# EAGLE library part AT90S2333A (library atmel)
MICROCONTROLLER 2 Kbytes FLASH 128 bytes SRAM 128 bytes EEPROM UART 6-channel 10-bit ADC

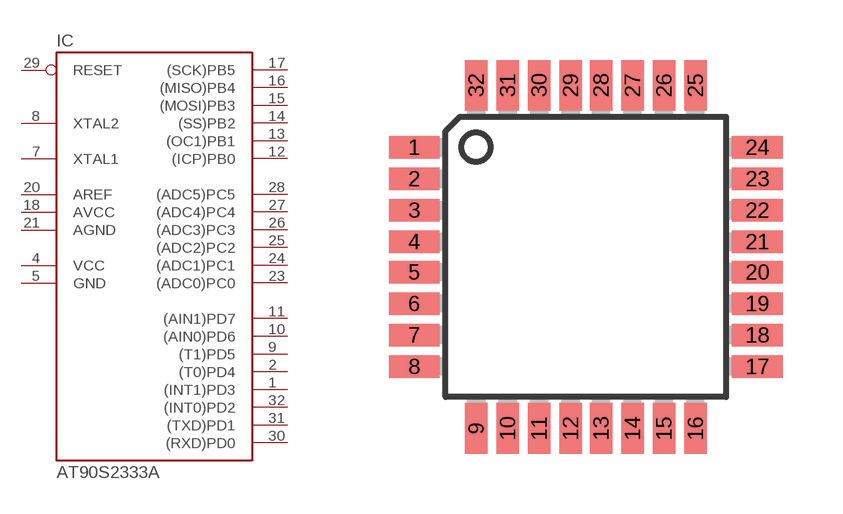
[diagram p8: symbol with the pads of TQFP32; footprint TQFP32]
Designator prefix IC

## AT90S2333A  [TQFP32]
1  (INT1)PD3
2  (T0)PD4
3  NC1  nc
4  VCC  pwr
5  GND  pwr
6  NC2  nc
7  XTAL1
8  XTAL2
9  (T1)PD5
10  (AIN0)PD6
11  (AIN1)PD7
12  (ICP)PB0
13  (OC1)PB1
14  (SS)PB2
15  (MOSI)PB3
16  (MISO)PB4
17  (SCK)PB5
18  AVCC  pwr
19  NC3  nc
20  AREF  pwr
21  AGND  pwr
22  NC4  nc
23  (ADC0)PC0
24  (ADC1)PC1
25  (ADC2)PC2
26  (ADC3)PC3
27  (ADC4)PC4
28  (ADC5)PC5
29  RESET  in
30  (RXD)PD0
31  (TXD)PD1
32  (INT0)PD2

## Footprint TQFP32 (pad centres in mm)
Thin Plasic Quad Flat Package
smd 1.27 x 0.559: 1 -4.293,2.743; 2 -4.293,1.956; 3 -4.293,1.168; 4 -4.293,0.381; 5 -4.293,-0.381; 6 -4.293,-1.168; 7 -4.293,-1.956; 8 -4.293,-2.743; 17 4.293,-2.743; 18 4.293,-1.956; 19 4.293,-1.168; 20 4.293,-0.381; 21 4.293,0.381; 22 4.293,1.168; 23 4.293,1.956; 24 4.293,2.743
smd 0.559 x 1.27: 9 -2.743,-4.293; 10 -1.956,-4.293; 11 -1.168,-4.293; 12 -0.381,-4.293; 13 0.381,-4.293; 14 1.168,-4.293; 15 1.956,-4.293; 16 2.743,-4.293; 25 2.743,4.293; 26 1.956,4.293; 27 1.168,4.293; 28 0.381,4.293; 29 -0.381,4.293; 30 -1.168,4.293; 31 -1.956,4.293; 32 -2.743,4.293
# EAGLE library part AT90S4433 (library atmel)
MICROCONTROLLER 4 Kbytes FLASH 128 bytes SRAM 256 bytes EEPROM UART 6-channel 10 bit ADC

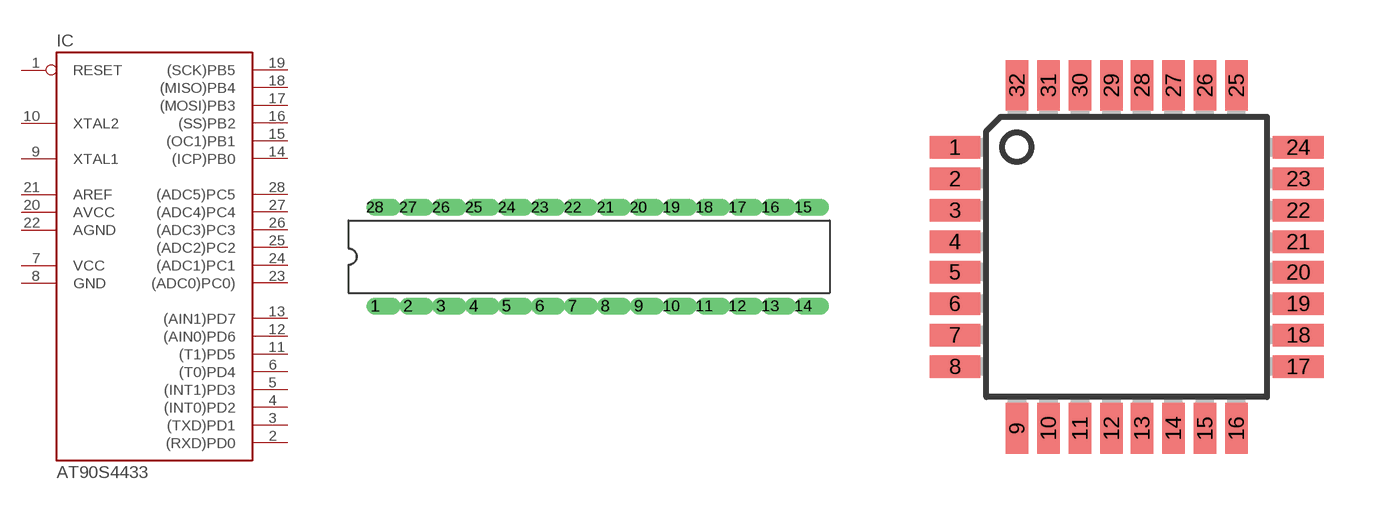
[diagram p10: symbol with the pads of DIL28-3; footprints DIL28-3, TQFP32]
Designator prefix IC

## AT90S4433P  [DIL28-3]
1  RESET  in
2  (RXD)PD0
3  (TXD)PD1
4  (INT0)PD2
5  (INT1)PD3
6  (T0)PD4
7  VCC  pwr
8  GND  pwr
9  XTAL1
10  XTAL2
11  (T1)PD5
12  (AIN0)PD6
13  (AIN1)PD7
14  (ICP)PB0
15  (OC1)PB1
16  (SS)PB2
17  (MOSI)PB3
18  (MISO)PB4
19  (SCK)PB5
20  AVCC  pwr
21  AREF  pwr
22  AGND  pwr
23  (ADC0)PC0)
24  (ADC1)PC1
25  (ADC2)PC2
26  (ADC3)PC3
27  (ADC4)PC4
28  (ADC5)PC5

## AT90S4433A  [TQFP32]
1  (INT1)PD3
2  (T0)PD4
4  VCC  pwr
5  GND  pwr
7  XTAL1
8  XTAL2
9  (T1)PD5
10  (AIN0)PD6
11  (AIN1)PD7
12  (ICP)PB0
13  (OC1)PB1
14  (SS)PB2
15  (MOSI)PB3
16  (MISO)PB4
17  (SCK)PB5
18  AVCC  pwr
20  AREF  pwr
21  AGND  pwr
23  (ADC0)PC0)
24  (ADC1)PC1
25  (ADC2)PC2
26  (ADC3)PC3
27  (ADC4)PC4
28  (ADC5)PC5
29  RESET  in
30  (RXD)PD0
31  (TXD)PD1
32  (INT0)PD2

## Footprint DIL28-3 (pad centres in mm)
Dual In Line 0.3 inch
drill 0.813 offset: 1 -16.51,-3.81; 2 -13.97,-3.81; 3 -11.43,-3.81; 4 -8.89,-3.81; 5 -6.35,-3.81; 6 -3.81,-3.81; 7 -1.27,-3.81; 8 1.27,-3.81; 9 3.81,-3.81; 10 6.35,-3.81; 11 8.89,-3.81; 12 11.43,-3.81; 13 13.97,-3.81; 14 16.51,-3.81; 15 16.51,3.81; 16 13.97,3.81; 17 11.43,3.81; 18 8.89,3.81; 19 6.35,3.81; 20 3.81,3.81; 21 1.27,3.81; 22 -1.27,3.81; 23 -3.81,3.81; 24 -6.35,3.81; 25 -8.89,3.81; 26 -11.43,3.81; 27 -13.97,3.81; 28 -16.51,3.81

## Footprint TQFP32 (pad centres in mm)
Thin Plasic Quad Flat Package
smd 1.27 x 0.559: 1 -4.293,2.743; 2 -4.293,1.956; 3 -4.293,1.168; 4 -4.293,0.381; 5 -4.293,-0.381; 6 -4.293,-1.168; 7 -4.293,-1.956; 8 -4.293,-2.743; 17 4.293,-2.743; 18 4.293,-1.956; 19 4.293,-1.168; 20 4.293,-0.381; 21 4.293,0.381; 22 4.293,1.168; 23 4.293,1.956; 24 4.293,2.743
smd 0.559 x 1.27: 9 -2.743,-4.293; 10 -1.956,-4.293; 11 -1.168,-4.293; 12 -0.381,-4.293; 13 0.381,-4.293; 14 1.168,-4.293; 15 1.956,-4.293; 16 2.743,-4.293; 25 2.743,4.293; 26 1.956,4.293; 27 1.168,4.293; 28 0.381,4.293; 29 -0.381,4.293; 30 -1.168,4.293; 31 -1.956,4.293; 32 -2.743,4.293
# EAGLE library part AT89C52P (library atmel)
MICROCONTROLLER 8 Kbytes FLASH

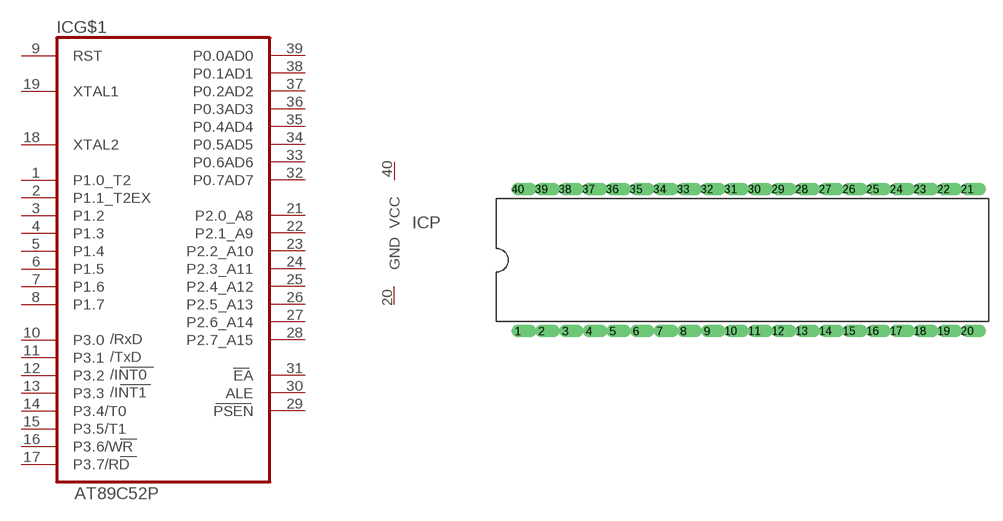
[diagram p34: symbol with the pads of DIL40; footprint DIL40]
Designator prefix IC; gates G$1=AT89C52 P=VCCGND

## AT89C52P  [DIL40]
1  G$1:P1.0_T2
2  G$1:P1.1_T2EX
3  G$1:P1.2
4  G$1:P1.3
5  G$1:P1.4
6  G$1:P1.5
7  G$1:P1.6
8  G$1:P1.7
9  G$1:RST  in
10  G$1:P3.0
11  G$1:P3.1
12  G$1:P3.2
13  G$1:P3.3
14  G$1:P3.4/T0
15  G$1:P3.5/T1
16  G$1:P3.6/WR
17  G$1:P3.7/RD
18  G$1:XTAL2  in
19  G$1:XTAL1  in
20  P:GND  pwr
21  G$1:P2.0_A8
22  G$1:P2.1_A9
23  G$1:P2.2_A10
24  G$1:P2.3_A11
25  G$1:P2.4_A12
26  G$1:P2.5_A13
27  G$1:P2.6_A14
28  G$1:P2.7_A15
29  G$1:PSEN  out
30  G$1:ALE  out
31  G$1:EA  in
32  G$1:P0.7AD7
33  G$1:P0.6AD6
34  G$1:P0.5AD5
35  G$1:P0.4AD4
36  G$1:P0.3AD3
37  G$1:P0.2AD2
38  G$1:P0.1AD1
39  G$1:P0.0AD0
40  P:VCC  pwr

## Footprint DIL40 (pad centres in mm)
Dual In Line
drill 0.813 offset: 1 -24.13,-7.62; 2 -21.59,-7.62; 3 -19.05,-7.62; 4 -16.51,-7.62; 5 -13.97,-7.62; 6 -11.43,-7.62; 7 -8.89,-7.62; 8 -6.35,-7.62; 9 -3.81,-7.62; 10 -1.27,-7.62; 11 1.27,-7.62; 12 3.81,-7.62; 13 6.35,-7.62; 14 8.89,-7.62; 15 11.43,-7.62; 16 13.97,-7.62; 17 16.51,-7.62; 18 19.05,-7.62; 19 21.59,-7.62; 20 24.13,-7.62; 21 24.13,7.62; 22 21.59,7.62; 23 19.05,7.62; 24 16.51,7.62; 25 13.97,7.62; 26 11.43,7.62; 27 8.89,7.62; 28 6.35,7.62; 29 3.81,7.62; 30 1.27,7.62; 31 -1.27,7.62; 32 -3.81,7.62; 33 -6.35,7.62; 34 -8.89,7.62; 35 -11.43,7.62; 36 -13.97,7.62; 37 -16.51,7.62; 38 -19.05,7.62; 39 -21.59,7.62; 40 -24.13,7.62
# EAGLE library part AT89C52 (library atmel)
MICROCONTROLLER 8 Kbytes FLASH

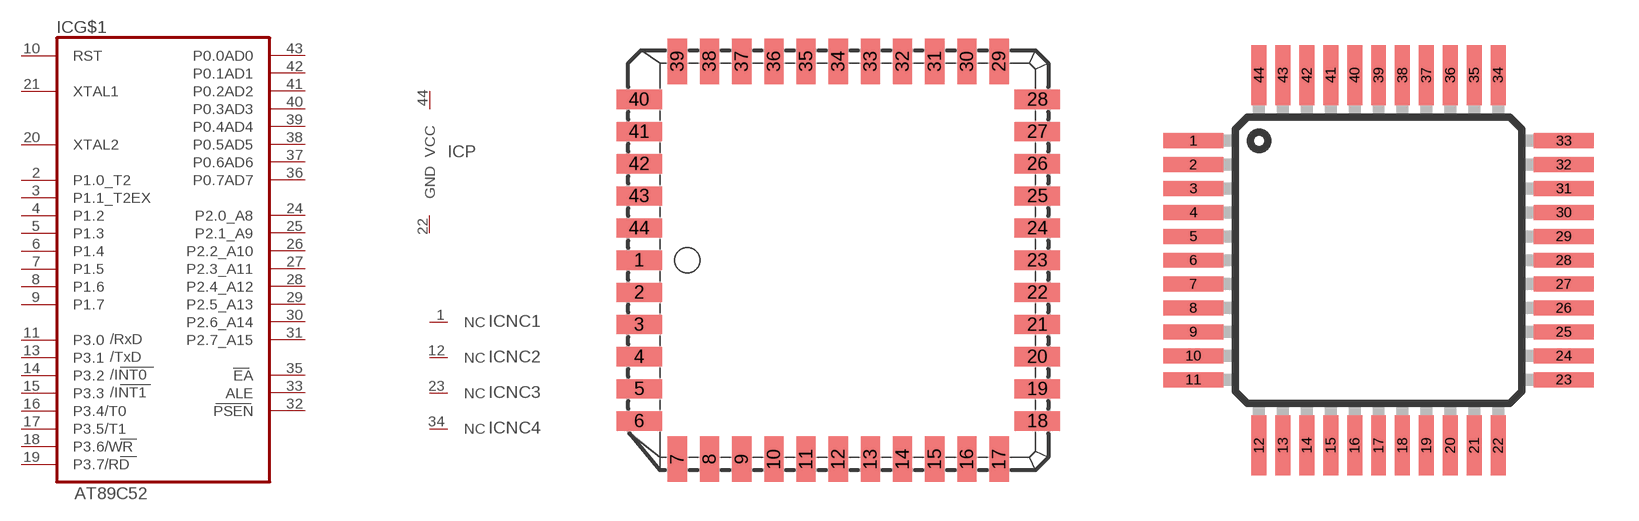
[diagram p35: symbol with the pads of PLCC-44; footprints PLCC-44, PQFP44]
Designator prefix IC; gates G$1=AT89C52 P=VCCGND NC1=NC NC2=NC NC3=NC NC4=NC

## AT89C52J  [PLCC-44]
1  NC1:NC  nc
2  G$1:P1.0_T2
3  G$1:P1.1_T2EX
4  G$1:P1.2
5  G$1:P1.3
6  G$1:P1.4
7  G$1:P1.5
8  G$1:P1.6
9  G$1:P1.7
10  G$1:RST  in
11  G$1:P3.0
12  NC2:NC  nc
13  G$1:P3.1
14  G$1:P3.2
15  G$1:P3.3
16  G$1:P3.4/T0
17  G$1:P3.5/T1
18  G$1:P3.6/WR
19  G$1:P3.7/RD
20  G$1:XTAL2  in
21  G$1:XTAL1  in
22  P:GND  pwr
23  NC3:NC  nc
24  G$1:P2.0_A8
25  G$1:P2.1_A9
26  G$1:P2.2_A10
27  G$1:P2.3_A11
28  G$1:P2.4_A12
29  G$1:P2.5_A13
30  G$1:P2.6_A14
31  G$1:P2.7_A15
32  G$1:PSEN  out
33  G$1:ALE  out
34  NC4:NC  nc
35  G$1:EA  in
36  G$1:P0.7AD7
37  G$1:P0.6AD6
38  G$1:P0.5AD5
39  G$1:P0.4AD4
40  G$1:P0.3AD3
41  G$1:P0.2AD2
42  G$1:P0.1AD1
43  G$1:P0.0AD0
44  P:VCC  pwr

## AT89C52Q  [PQFP44]
1  G$1:P1.5
2  G$1:P1.6
3  G$1:P1.7
4  G$1:RST  in
5  G$1:P3.0
6  NC1:NC  nc
7  G$1:P3.1
8  G$1:P3.2
9  G$1:P3.3
10  G$1:P3.4/T0
11  G$1:P3.5/T1
12  G$1:P3.6/WR
13  G$1:P3.7/RD
14  G$1:XTAL2  in
15  G$1:XTAL1  in
16  P:GND  pwr
17  NC2:NC  nc
18  G$1:P2.0_A8
19  G$1:P2.1_A9
20  G$1:P2.2_A10
21  G$1:P2.3_A11
22  G$1:P2.4_A12
23  G$1:P2.5_A13
24  G$1:P2.6_A14
25  G$1:P2.7_A15
26  G$1:PSEN  out
27  G$1:ALE  out
28  NC3:NC  nc
29  G$1:EA  in
30  G$1:P0.7AD7
31  G$1:P0.6AD6
32  G$1:P0.5AD5
33  G$1:P0.4AD4
34  G$1:P0.3AD3
35  G$1:P0.2AD2
36  G$1:P0.1AD1
37  G$1:P0.0AD0
38  P:VCC  pwr
39  NC4:NC  nc
40  G$1:P1.0_T2
41  G$1:P1.1_T2EX
42  G$1:P1.2
43  G$1:P1.3
44  G$1:P1.4

## AT89C52A  [TQFP44]
Pads as for PQFP44

## Footprint PLCC-44 (pad centres in mm)
Plastic J-Leaded Chip Carrier
smd 1.8 x 0.76: 1 -7.86,0; 2 -7.86,-1.27; 3 -7.86,-2.54; 4 -7.86,-3.81; 5 -7.86,-5.08; 6 -7.86,-6.35; 18 7.86,-6.35; 19 7.86,-5.08; 20 7.86,-3.81; 21 7.86,-2.54; 22 7.86,-1.27; 23 7.86,0; 24 7.86,1.27; 25 7.86,2.54; 26 7.86,3.81; 27 7.86,5.08; 28 7.86,6.35; 40 -7.86,6.35; 41 -7.86,5.08; 42 -7.86,3.81; 43 -7.86,2.54; 44 -7.86,1.27
smd 0.76 x 1.8: 7 -6.35,-7.86; 8 -5.08,-7.86; 9 -3.81,-7.86; 10 -2.54,-7.86; 11 -1.27,-7.86; 12 0,-7.86; 13 1.27,-7.86; 14 2.54,-7.86; 15 3.81,-7.86; 16 5.08,-7.86; 17 6.35,-7.86; 29 6.35,7.86; 30 5.08,7.86; 31 3.81,7.86; 32 2.54,7.86; 33 1.27,7.86; 34 0,7.86; 35 -1.27,7.86; 36 -2.54,7.86; 37 -3.81,7.86; 38 -5.08,7.86; 39 -6.35,7.86

## Footprint PQFP44 (pad centres in mm)
Plastic Quad Flat Package
smd 2 x 0.5: 1 -6.2,4; 2 -6.2,3.2; 3 -6.2,2.4; 4 -6.2,1.6; 5 -6.2,0.8; 6 -6.2,0; 7 -6.2,-0.8; 8 -6.2,-1.6; 9 -6.2,-2.4; 10 -6.2,-3.2; 11 -6.2,-4; 23 6.2,-4; 24 6.2,-3.2; 25 6.2,-2.4; 26 6.2,-1.6; 27 6.2,-0.8; 28 6.2,0; 29 6.2,0.8; 30 6.2,1.6; 31 6.2,2.4; 32 6.2,3.2; 33 6.2,4
smd 0.5 x 2: 12 -4,-6.2; 13 -3.2,-6.2; 14 -2.4,-6.2; 15 -1.6,-6.2; 16 -0.8,-6.2; 17 0,-6.2; 18 0.8,-6.2; 19 1.6,-6.2; 20 2.4,-6.2; 21 3.2,-6.2; 22 4,-6.2; 34 4,6.2; 35 3.2,6.2; 36 2.4,6.2; 37 1.6,6.2; 38 0.8,6.2; 39 0,6.2; 40 -0.8,6.2; 41 -1.6,6.2; 42 -2.4,6.2; 43 -3.2,6.2; 44 -4,6.2

## Footprint TQFP44 (pad centres in mm)
Thin Plasic Quad Flat Package
smd 1.5 x 0.5: 1 -5.8,4; 2 -5.8,3.2; 3 -5.8,2.4; 4 -5.8,1.6; 5 -5.8,0.8; 6 -5.8,0; 7 -5.8,-0.8; 8 -5.8,-1.6; 9 -5.8,-2.4; 10 -5.8,-3.2; 11 -5.8,-4; 23 5.8,-4; 24 5.8,-3.2; 25 5.8,-2.4; 26 5.8,-1.6; 27 5.8,-0.8; 28 5.8,0; 29 5.8,0.8; 30 5.8,1.6; 31 5.8,2.4; 32 5.8,3.2; 33 5.8,4
smd 0.5 x 1.5: 12 -4,-5.8; 13 -3.2,-5.8; 14 -2.4,-5.8; 15 -1.6,-5.8; 16 -0.8,-5.8; 17 0,-5.8; 18 0.8,-5.8; 19 1.6,-5.8; 20 2.4,-5.8; 21 3.2,-5.8; 22 4,-5.8; 34 4,5.8; 35 3.2,5.8; 36 2.4,5.8; 37 1.6,5.8; 38 0.8,5.8; 39 0,5.8; 40 -0.8,5.8; 41 -1.6,5.8; 42 -2.4,5.8; 43 -3.2,5.8; 44 -4,5.8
